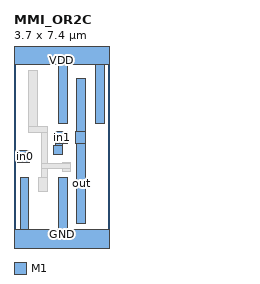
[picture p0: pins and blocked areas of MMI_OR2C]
MACRO MMI_OR2C
	CLASS CORE ;
	FOREIGN MMI_OR2C 0 0 ;
	SIZE 3.7 BY 7.4 ;
	SYMMETRY X Y ;
	SITE CORE1 ;
	PIN out
		DIRECTION output ;
		USE SIGNAL ;
		PORT
			LAYER M1 ;
			RECT 2.45 4.295 2.79 6.37 ;
			LAYER M1 ;
			RECT 2.395 3.845 2.79 4.295 ;
			LAYER M1 ;
			RECT 2.45 0.74 2.79 3.845 ;
		END
		AntennaDiffArea 1.8768 ;
	END out
	PIN in1
		DIRECTION input ;
		USE SIGNAL ;
		PORT
			LAYER M1 ;
			RECT 1.625 3.845 2.075 4.295 ;
			LAYER M1 ;
			RECT 1.625 3.755 1.875 3.845 ;
			LAYER M1 ;
			RECT 1.535 3.415 1.875 3.755 ;
		END
		AntennaGateArea 0.558 ;
	END in1
	PIN GND
		DIRECTION inout ;
		USE GROUND ;
		PORT
			LAYER M1 ;
			RECT 0.24 0.5 0.58 2.5 ;
			LAYER M1 ;
			RECT 1.73 0.5 2.07 2.5 ;
			LAYER M1 ;
			RECT 0 -0.5 3.7 0.5 ;
		END
	END GND
	PIN VDD
		DIRECTION inout ;
		USE POWER ;
		PORT
			LAYER M1 ;
			RECT 0 6.9 3.7 7.9 ;
			LAYER M1 ;
			RECT 1.73 4.61 2.07 6.9 ;
			LAYER M1 ;
			RECT 3.17 4.61 3.51 6.9 ;
		END
	END VDD
	PIN in0
		DIRECTION input ;
		USE SIGNAL ;
		PORT
			LAYER M1 ;
			RECT 0.145 3.5 0.595 3.555 ;
			LAYER M1 ;
			RECT 0.145 3.16 0.665 3.5 ;
			LAYER M1 ;
			RECT 0.145 3.105 0.595 3.16 ;
		END
		AntennaGateArea 0.558 ;
	END in0
	OBS
		LAYER M1 ;
		RECT 0.57 4.5 0.91 6.67 ;
		LAYER M1 ;
		RECT 0.57 4.27 1.3 4.5 ;
		LAYER M1 ;
		RECT 1.07 3.075 1.3 4.27 ;
		LAYER M1 ;
		RECT 1.87 3.075 2.21 3.08 ;
		LAYER M1 ;
		RECT 1.07 2.845 2.21 3.075 ;
		LAYER M1 ;
		RECT 1.07 2.5 1.3 2.845 ;
		LAYER M1 ;
		RECT 1.87 2.74 2.21 2.845 ;
		LAYER M1 ;
		RECT 0.96 1.96 1.3 2.5 ;
	END
END MMI_OR2C
